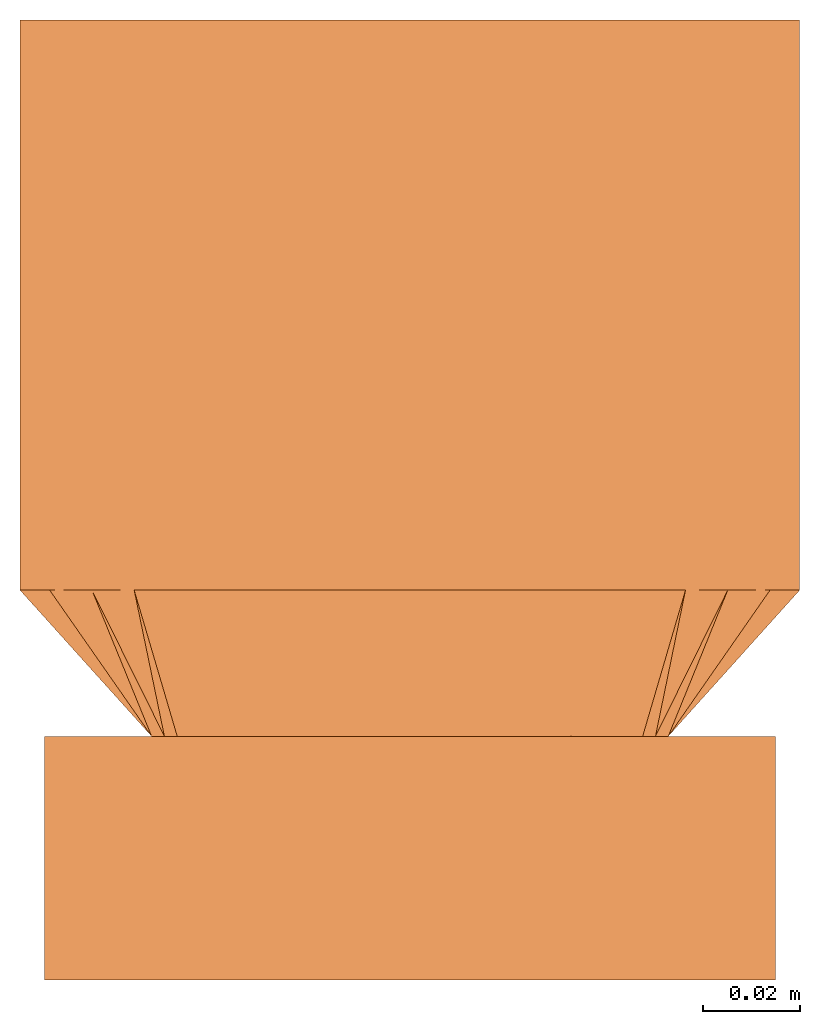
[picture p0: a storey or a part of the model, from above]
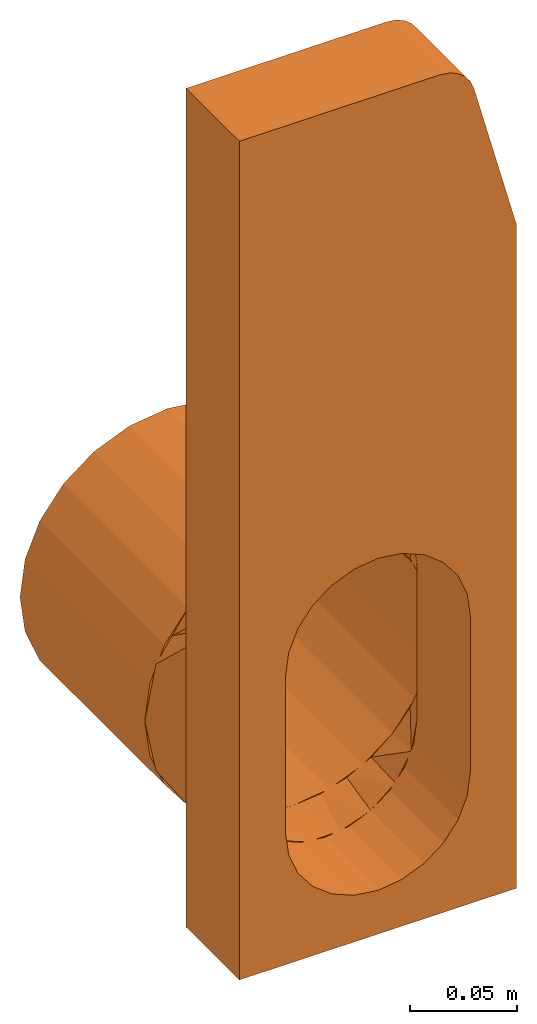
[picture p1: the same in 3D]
Properties of the parts of a building model (IFC2X3)

# File
Description: ViewDefinition [CoordinationView]
File name: 4940 - RH inlet or outlet end cap.ifc
Time: 2013-09-18T16:25:42
Written by: Autodesk Revit 2013
Made in: 20120221_2030(x64)

# IfcProject, Project Number
LongName: Project Name; Phase: Project Status

# IfcSite, Default
RefLatitude: 42, 21, 30, 344238; RefLongitude: -71, -3, -35, -194702; RefElevation: 0 mm

# IfcBuilding
Pset_BuildingCommon - NumberOfStoreys: 2
Other - Project Number: Project Number; Project Issue Date: Issue Date; Project Status: Project Status; Project Name: Project Name; Client Name: Owner; Project Address: Enter address here

# IfcBuildingStorey (2)
Constraints - Elevation Base: 0
Graphics - Line Pattern: Center; Symbol at End 2 Default: yes; Line Weight: 1; Symbol at End 1 Default: no; Color: 0; Symbol: M_Level Head - Circle: M_Level Head - Circle
Identity Data - Structural: no; Building Story: yes
Dimensions - Computation Height: 0 mm
Name | LongName = Name | Elevation (mm) = Constraints, Elevation (mm)
T.O. Fnd. Wall | T.O. Fnd. Wall | -300
Level 1 | Level 1 | 0

# IfcBuildingElementProxy: 4940 - RH inlet/outlet end cap, Civil-Drainage-Channel-ACO-KerbDrain-HB480(amar):4940 - RH inlet/outlet end cap:4940 - RH inlet/outlet end cap:481515
In: T.O. Fnd. Wall
Material: Acetal Resin, Black, ACO Polymer Concrete.
Other - Revision: 1; CreatedBy: www.aco.co.uk
Green Building Properties - Channel Recycled Material Content: N/A; End Cap Recyclable: Fully recyclable; End Cap Recycled Material Content: 20% minimum; Access Cover/Frame Recycled Material Content: N/A; Access Cover/Frame Recyclable: N/A; Channel Recyclable: N/A
Construction - cable loop: no; 10-8m external mitre: no; RH inlet/outlet end cap: yes; 25-11m internal mitre: no; LH drop kerb: no; Junction channel: no; Closing end cap: no; RH drop kerb: no; 7-6m external mitre: no; HB480-500: no; Bus stop kerb: no; perforated centre stone: no; LH inlet/outlet end cap: no; Junction end cap: no; Access Unit: no; 25-11m external mitre: no; Centre Stone: no; LH BS transition kerb: no; RH BS transition kerb: no; KDHB480 500_blindunit: no; Junction access unit: no
Constraints - Level: Level: Level 1; Moves With Nearby Elements: no
Phasing - Phase Created: Phase 1
Dimensions - Volume: 2938037 mm3; Mitre Small End: 487 mm; I/O endcap void depth: 333.6 mm; Mitre Void End: -4570 mm; Void Length: 50 mm; Void Start I/O: -5.1 mm; junction void depth: 2000 mm; Void Width: 150 mm; Mitre Long end: 500 mm; Junction End: 2 mm; Mitre Void Start: -4565 mm; Junction Start: 0 mm; Straight Void Start: 0 mm; Void Depth: -355 mm; Void End I/O: 155.1 mm
Pset_BuildingElementProxyCommon - Reference: 4940 - RH inlet/outlet end cap
Identity Data - Price: POA - contact ACO; URL: www.aco.co.uk; e-mail Sales: customersupport@aco.co.uk; Assembly Code: D2040; Product brochure: http://www.aco.co.uk/download.php?id=120; Manufacturer: ACO Technologies plc - ACO Water Management Division; Fax: +44 (0)1462 815895; OmniClass Title: Rainwater Removal; Telephone: +44 (0)1462 816666; OmniClass Number: 23.70.50.24; e-mail Technical: technical@aco.co.uk; Product Page URL: http://www.aco.co.uk/product_detail.php?id=3; Address: ACO Business Park, Hitchin Road, Shefford, Bedfordshire, United Kingdom SG17 5TE; Installation guidelines: http://www.aco.co.uk/download.php?id=120; Model Description: Combined kerb and drainage system; Model: ACO KerbDrain HB480; Assembly Description: Rain Water Drainage; Type Comments: ACO KerbDrain HB480 half battered RH outlet end cap; Maintenance guidelines: http://www.aco.co.uk/download.php?id=120; Cost: 0; Product Code: 4940
General - SerialNumber: 0.000000; TagNumber: 0.000000
Materials and Finishes - End Cap Colour: Grey; Connection Pipe Material: Medium Density Polyethylene; Access Cover/Frame Colour: N/A; End Cap Material: Vienite® Synthetic Resin Concrete; Connection Pipe Material Colour: Black; Channel Colour: N/A; Channel Material: N/A; Access Cover/Frame Finish: N/A; Access Cover/Frame Material: N/A
Data - Installation - Concrete Grade: N/A; Product Dimensions: 50mm x 150mm x 480mm (LxWxH); Invert Depth: N/A; Product Weight: 5.9 Kg; Connection Pipe O.D: Ø160mm; Hydraulic Performance: N/A; Channel C.S.A: N/A; Load Class: N/A; Concrete Surround Volume - Load Class A 15 - D 400 - Concrete Pavement: N/A; Product Standard: N/A; ACO Hydraulic Design Software: N/A; Drainage Slot Intake area: N/A; Concrete Surround Volume - Load Class A 15 - D 400 - Grass or Asphalt Pavement: N/A; Drainage Slot Width: N/A

# IfcOpeningElement: Opening (3)
In: Level 1
Dimensions - Perimeter: 9790 mm; Area: 5901750 mm2; Volume: 2354181020 mm3; Thickness: 400 mm
Phasing - Phase Created: Phase 1
Constraints - Room Bounding: yes; Related to Mass: no; Height Offset From Level: 0 mm; Level: Level: Level 1
Structural - Enable Analytical Model: no; Structural: no
Analytical Properties - Roughness: 1; Heat Transfer Coefficient (U): 2.0925; Thermal Resistance (R): 0.477897; Absorptance: 0.1; Thermal mass: 543920
Graphics - Coarse Scale Fill Color: 0
Construction - Function: 0; Default Thickness: 400 mm
Materials and Finishes - Structural Material: Earth

# IfcSlab: Floor:Generic Floor - 400mm, Floor:Generic Floor - 400mm:136426
In: Level 1
PredefinedType: FLOOR; Material: Earth 400 mm
Dimensions - Perimeter: 9790 mm; Area: 5901750 mm2; Volume: 2354181020 mm3; Thickness: 400 mm
Phasing - Phase Created: Phase 1
Constraints - Room Bounding: yes; Related to Mass: no; Height Offset From Level: 0 mm; Level: Level: Level 1
Structural - Enable Analytical Model: no; Structural: no
Pset_SlabCommon - Reference: Generic Floor - 400mm; IsExternal: no; LoadBearing: yes
Analytical Properties - Roughness: 1; Heat Transfer Coefficient (U): 2.0925; Thermal Resistance (R): 0.477897; Absorptance: 0.1; Thermal mass: 543920
Graphics - Coarse Scale Fill Color: 0
Construction - Function: 0; Default Thickness: 400 mm
Materials and Finishes - Structural Material: Earth
